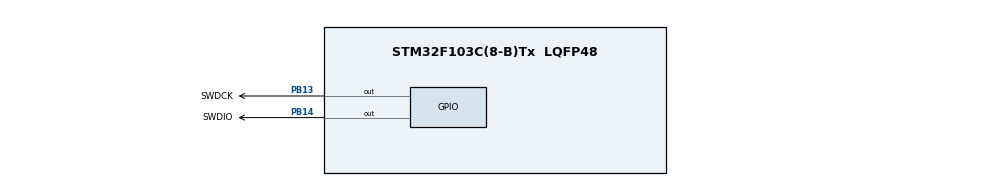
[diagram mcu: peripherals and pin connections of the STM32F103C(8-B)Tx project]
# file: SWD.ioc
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Mcu.Family=STM32F1
Mcu.Name=STM32F103C(8-B)Tx
Mcu.Package=LQFP48
NVIC.PriorityGroup=NVIC_PRIORITYGROUP_4
PA13.Mode=Serial_Wire
PA13.Signal=SYS_JTMS-SWDIO
PA14.Mode=Serial_Wire
PA14.Signal=SYS_JTCK-SWCLK
PB13.GPIO_Label=SWDCK
PB13.Signal=GPIO_Output
PB14.GPIO_Label=SWDIO
PB14.Signal=GPIO_Output
PD0-OSC_IN.Mode=HSE-External-Oscillator
PD0-OSC_IN.Signal=RCC_OSC_IN
PD1-OSC_OUT.Mode=HSE-External-Oscillator
PD1-OSC_OUT.Signal=RCC_OSC_OUT
ProjectManager.HeapSize=0x200
ProjectManager.StackSize=0x400
ProjectManager.TargetToolchain=SW4STM32
RCC.APB1Freq_Value=8000000
RCC.APB2Freq_Value=8000000
board=custom

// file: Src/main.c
/**
  ******************************************************************************
  * @file           : main.c
  * @brief          : Main program body
  ******************************************************************************
  ** This notice applies to any and all portions of this file
  * that are not between comment pairs USER CODE BEGIN and
  * USER CODE END. Other portions of this file, whether
  * inserted by the user or by software development tools
  * are owned by their respective copyright owners.
  *
  * COPYRIGHT(c) 2019 STMicroelectronics
  *
  * Redistribution and use in source and binary forms, with or without modification,
  * are permitted provided that the following conditions are met:
  *   1. Redistributions of source code must retain the above copyright notice,
  *      this list of conditions and the following disclaimer.
  *   2. Redistributions in binary form must reproduce the above copyright notice,
  *      this list of conditions and the following disclaimer in the documentation
  *      and/or other materials provided with the distribution.
  *   3. Neither the name of STMicroelectronics nor the names of its contributors
  *      may be used to endorse or promote products derived from this software
  *      without specific prior written permission.
  *
  * THIS SOFTWARE IS PROVIDED BY THE COPYRIGHT HOLDERS AND CONTRIBUTORS "AS IS"
  * AND ANY EXPRESS OR IMPLIED WARRANTIES, INCLUDING, BUT NOT LIMITED TO, THE
  * IMPLIED WARRANTIES OF MERCHANTABILITY AND FITNESS FOR A PARTICULAR PURPOSE ARE
  * DISCLAIMED. IN NO EVENT SHALL THE COPYRIGHT HOLDER OR CONTRIBUTORS BE LIABLE
  * FOR ANY DIRECT, INDIRECT, INCIDENTAL, SPECIAL, EXEMPLARY, OR CONSEQUENTIAL
  * DAMAGES (INCLUDING, BUT NOT LIMITED TO, PROCUREMENT OF SUBSTITUTE GOODS OR
  * SERVICES; LOSS OF USE, DATA, OR PROFITS; OR BUSINESS INTERRUPTION) HOWEVER
  * CAUSED AND ON ANY THEORY OF LIABILITY, WHETHER IN CONTRACT, STRICT LIABILITY,
  * OR TORT (INCLUDING NEGLIGENCE OR OTHERWISE) ARISING IN ANY WAY OUT OF THE USE
  * OF THIS SOFTWARE, EVEN IF ADVISED OF THE POSSIBILITY OF SUCH DAMAGE.
  *
  ******************************************************************************
  */
#include "main.h"
#include "stm32f1xx_hal.h"

/* USER CODE BEGIN Includes */
#include "swdLowLevel.h"
#include "SWD.h"
#include "FlashProgramming.h"
#include "CException.h"
#include "Exception.h"
/* USER CODE END Includes */

/* USER CODE BEGIN PV */
/* Private variables ---------------------------------------------------------*/

/* USER CODE END PV */

void SystemClock_Config(void);
static void MX_GPIO_Init(void);

/* USER CODE BEGIN PFP */
/* Private function prototypes -----------------------------------------------*/

/* USER CODE END PFP */

/* USER CODE BEGIN 0 */

void swdMassErase()
{
	uint32_t PageError;
	HAL_FLASH_Unlock();
	HAL_FLASHEx_Erase(FLASH_TYPEERASE_MASSERASE, &PageError);
	HAL_FLASH_Lock();
}

// Page erase ==> FLASH_PageErase(uint32_t PageAddress)
void swdPageErase(uint32_t pageAddress, int numOfSector)
{
	HAL_FLASH_Unlock();
	for(int i=0 ; i<numOfSector ; i++)
	{
		FLASH_PageErase(pageAddress);
		pageAddress+=FLASH_PAGE_SIZE;
	}
	HAL_FLASH_Lock();
}
/* USER CODE END 0 */

int main(void)
{
  /* USER CODE BEGIN 1 */
	volatile uint32_t ID, IDR_val, CPU_ID, data, csw;
	CEXCEPTION_T ex;
	volatile int doMassErase=0;
	volatile int doPageErase=0;
	volatile uint32_t buffer1[128];
	uint32_t *dst = buffer1;

	if(doPageErase) {
	  swdPageErase(0x8006000, 2);
	}

	if(doMassErase) {
	  swdMassErase();
	}
  /* USER CODE END 1 */

  /* MCU Configuration----------------------------------------------------------*/

  /* Reset of all peripherals, Initializes the Flash interface and the Systick. */
  HAL_Init();

  /* Configure the system clock */
  SystemClock_Config();

  /* Initialize all configured peripherals */
  MX_GPIO_Init();
  /* USER CODE BEGIN 2 */
  Try{
  swdWriteBits(0b101010, 6);
  ID = swdInitTap();
  IDR_val = initAHB_AP();
  csw = swdReadAP(AHB_AP, AHB_AP_CSW);
  CPU_ID = swdReadMem32(0xE0042000);
  CPU_ID = swdReadMem32(0xE000ED00);

  data = swdSystemResetAndHaltCore();
  //swdWriteMem32(0x20001010, 0x12345678);
  //swdWriteMem32(0x20001014, 0xbadface);
  data = swdReadMem32(0x20001010);
  data = swdReadMem32(0x20001014);
  data = swdReadMem32(0x8000000);

  swdWriteCoreReg(R5, 0xfe110);
  data = swdReadCoreReg(R5);

  swdUnhaltCore();
  swdWriteMem32(0x20001010, 0x98765432);
  swdWriteMem32(0x20001014, 0xbadface);
  data = swdReadMem32(0x20001010);
  data = swdReadMem32(0x20001014);

  data = swdReadMem32(0x8000000);
  swdWriteFlash(0x8006100, "hello world", 12);
  swdReadMemBlock(&dst, swdReadMem32(&monitorState->dataAddr), 12);
  swdReadMemBlock(&dst, 0x8006100, 12);

  HAL_FLASH_Unlock();
  FLASH_PageErase(0x08001000);
  swdWritePacket(AP, 0xcd, 0x12345678);	// dummy
  } Catch (ex) {
	  freeError(ex);
  }
  /* USER CODE END 2 */

  /* Infinite loop */
  while (1)
  {

  }

}

void SystemClock_Config(void)
{

  RCC_OscInitTypeDef RCC_OscInitStruct;
  RCC_ClkInitTypeDef RCC_ClkInitStruct;

    /**Initializes the CPU, AHB and APB busses clocks
    */
  RCC_OscInitStruct.OscillatorType = RCC_OSCILLATORTYPE_HSE;
  RCC_OscInitStruct.HSEState = RCC_HSE_ON;
  RCC_OscInitStruct.HSEPredivValue = RCC_HSE_PREDIV_DIV1;
  RCC_OscInitStruct.HSIState = RCC_HSI_ON;
  RCC_OscInitStruct.PLL.PLLState = RCC_PLL_ON;
  RCC_OscInitStruct.PLL.PLLSource = RCC_PLLSOURCE_HSE;
  RCC_OscInitStruct.PLL.PLLMUL = RCC_PLL_MUL9;
  if (HAL_RCC_OscConfig(&RCC_OscInitStruct) != HAL_OK)
  {
    _Error_Handler(__FILE__, __LINE__);
  }

    /**Initializes the CPU, AHB and APB busses clocks
    */
  RCC_ClkInitStruct.ClockType = RCC_CLOCKTYPE_HCLK|RCC_CLOCKTYPE_SYSCLK
                              |RCC_CLOCKTYPE_PCLK1|RCC_CLOCKTYPE_PCLK2;
  RCC_ClkInitStruct.SYSCLKSource = RCC_SYSCLKSOURCE_PLLCLK;
  RCC_ClkInitStruct.AHBCLKDivider = RCC_SYSCLK_DIV1;
  RCC_ClkInitStruct.APB1CLKDivider = RCC_HCLK_DIV2;
  RCC_ClkInitStruct.APB2CLKDivider = RCC_HCLK_DIV1;

  if (HAL_RCC_ClockConfig(&RCC_ClkInitStruct, FLASH_LATENCY_2) != HAL_OK)
  {
    _Error_Handler(__FILE__, __LINE__);
  }

    /**Configure the Systick interrupt time
    */
  HAL_SYSTICK_Config(HAL_RCC_GetHCLKFreq()/1000);

    /**Configure the Systick
    */
  HAL_SYSTICK_CLKSourceConfig(SYSTICK_CLKSOURCE_HCLK);

  /* SysTick_IRQn interrupt configuration */
  HAL_NVIC_SetPriority(SysTick_IRQn, 0, 0);
}

/** Configure pins as
        * Analog
        * Input
        * Output
        * EVENT_OUT
        * EXTI
*/
static void MX_GPIO_Init(void)
{

  GPIO_InitTypeDef GPIO_InitStruct;

  /* GPIO Ports Clock Enable */
  __HAL_RCC_GPIOD_CLK_ENABLE();
  __HAL_RCC_GPIOB_CLK_ENABLE();
  __HAL_RCC_GPIOA_CLK_ENABLE();

  /*Configure GPIO pin Output Level */
  HAL_GPIO_WritePin(GPIOB, SWDCK_Pin|SWDIO_Pin, GPIO_PIN_RESET);

  /*Configure GPIO pins : SWDCK_Pin SWDIO_Pin TrN_Pin */
  GPIO_InitStruct.Pin = SWDCK_Pin|SWDIO_Pin;
  GPIO_InitStruct.Mode = GPIO_MODE_OUTPUT_PP;
  GPIO_InitStruct.Pull = GPIO_NOPULL;
  GPIO_InitStruct.Speed = GPIO_SPEED_FREQ_HIGH;
  HAL_GPIO_Init(GPIOB, &GPIO_InitStruct);

}

void _Error_Handler(char *file, int line)
{
  while(1)
  {
  }
}

/************************ (C) COPYRIGHT STMicroelectronics *****END OF FILE****/
